VERSION 5.8 ;
DIVIDERCHAR "/" ;
BUSBITCHARS "[]" ;
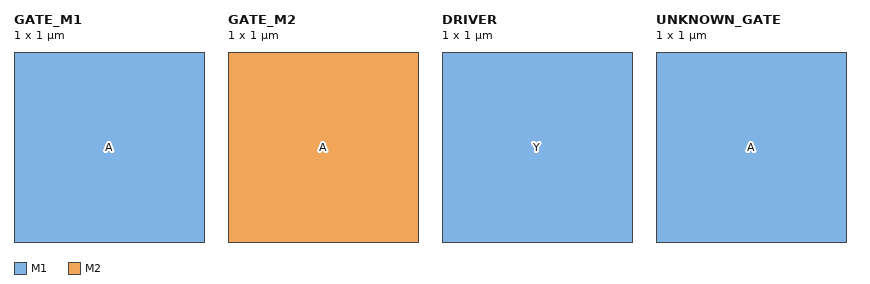
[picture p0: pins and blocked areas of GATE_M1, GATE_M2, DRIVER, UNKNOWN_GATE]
MACRO GATE_M1
  CLASS CORE ;
  ORIGIN 0 0 ;
  SIZE 1 BY 1 ;
  SITE CORE ;
  PIN A
    DIRECTION INPUT ;
    USE SIGNAL ;
    ANTENNAGATEAREA 1 LAYER M1 ;
    PORT
      LAYER M1 ;
        RECT 0 0 1 1 ;
    END
  END A
END GATE_M1
MACRO GATE_M2
  CLASS CORE ;
  ORIGIN 0 0 ;
  SIZE 1 BY 1 ;
  SITE CORE ;
  PIN A
    DIRECTION INPUT ;
    USE SIGNAL ;
    ANTENNAGATEAREA 1 LAYER M2 ;
    PORT
      LAYER M2 ;
        RECT 0 0 1 1 ;
    END
  END A
END GATE_M2
MACRO DRIVER
  CLASS CORE ;
  ORIGIN 0 0 ;
  SIZE 1 BY 1 ;
  SITE CORE ;
  PIN Y
    DIRECTION OUTPUT ;
    USE SIGNAL ;
    ANTENNADIFFAREA 0 LAYER M1 ;
    PORT
      LAYER M1 ;
        RECT 0 0 1 1 ;
    END
  END Y
END DRIVER
MACRO UNKNOWN_GATE
  CLASS CORE ;
  ORIGIN 0 0 ;
  SIZE 1 BY 1 ;
  SITE CORE ;
  PIN A
    DIRECTION INPUT ;
    USE SIGNAL ;
    PORT
      LAYER M1 ;
        RECT 0 0 1 1 ;
    END
  END A
END UNKNOWN_GATE
END LIBRARY
